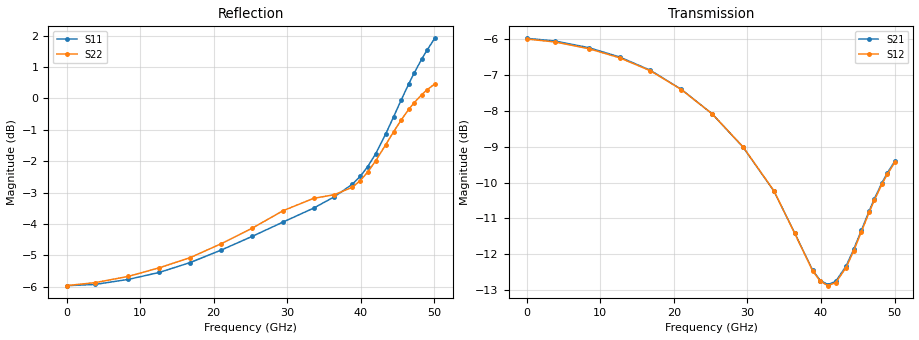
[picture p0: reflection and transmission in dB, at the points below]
! Touchstone file from project
! Exported from ElectronicsDesktop 2025.1.3
# GHz S MA R 50.000000
! Terminal data exported
! Port[1] = Port1
! Port[2] = Port2
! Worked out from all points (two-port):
!   144 points, 10 MHz to 50.05 GHz, reference 50 ohm
!   highest |S21| = -5.98 dB at 10 MHz (marker M1); lowest = -12.8 dB at 40.95 GHz (marker M2)
!   |S21| within 3 dB of the highest: start of sweep to 29.29 GHz
!   lowest |S11| = -6.0 dB at 10 MHz (marker M3), VSWR 3.03, Z = 150 - j13.7 ohm
!   |S11| at or under -10 dB: nowhere
!   |S22| runs from -6.0 to 0.5 dB; largest |S21 - S12| = 0.002
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0.01  0.5034 -3.9  0.5021 -4.7  0.501 -4.9  0.5036 -3.2
! Gamma 0 0 0 0
! Port Impedance 50 0 50 0
3.85945  0.5057 -7.0  0.4978 -8.1  0.4963 -8.1  0.509 -5.9
8.4088  0.5152 -12.6  0.4874 -14.7  0.4858 -14.7  0.5209 -11.2
12.6082  0.5285 -18.1  0.473 -21.7  0.4718 -21.7  0.5376 -15.9
16.8076  0.548 -23.0  0.4532 -28.6  0.4525 -28.6  0.558 -20.2
21.007  0.5735 -27.4  0.4263 -35.3  0.4261 -35.3  0.587 -24.1
25.2064  0.6029 -32.1  0.3941 -41.9  0.3941 -41.9  0.6212 -27.6
29.4058  0.6354 -36.6  0.3543 -47.4  0.3544 -47.5  0.6624 -31.7
33.6052  0.6691 -41.0  0.3077 -51.2  0.3078 -51.2  0.6934 -35.1
36.4048  0.6973 -43.5  0.2691 -50.7  0.269 -50.7  0.7026 -37.0
38.85445  0.7302 -45.3  0.2388 -46.4  0.2384 -46.4  0.722 -38.2
39.9043  0.7511 -46.0  0.231 -43.5  0.2304 -43.5  0.7394 -38.9
40.95415  0.779 -46.6  0.228 -40.3  0.2272 -40.3  0.7637 -39.8
42.004  0.8157 -47.0  0.2304 -37.2  0.2295 -37.2  0.7948 -40.8
43.4038  0.8784 -46.6  0.2419 -33.8  0.2407 -33.7  0.8443 -41.7
44.45365  0.9342 -45.3  0.2554 -32.4  0.2542 -32.3  0.8844 -41.7
45.5035  0.9946 -42.8  0.2716 -32.3  0.2703 -32.2  0.9243 -40.7
46.55335  1.056 -39.2  0.2888 -33.6  0.2875 -33.5  0.9616 -38.6
47.25325  1.097 -36.3  0.3002 -35.2  0.2988 -35.1  0.9842 -36.5
48.3031  1.156 -31.4  0.3162 -38.6  0.3149 -38.5  1.014 -32.7
49.003  1.193 -27.9  0.326 -41.4  0.3246 -41.3  1.032 -29.6
50.05285  1.246 -22.4  0.3389 -46.1  0.3376 -46.0  1.054 -24.6
